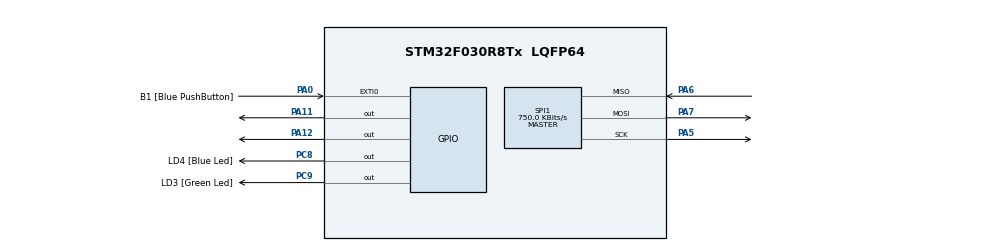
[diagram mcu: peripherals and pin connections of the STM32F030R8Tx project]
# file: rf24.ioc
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Mcu.Family=STM32F0
Mcu.Name=STM32F030R8Tx
Mcu.Package=LQFP64
PA0.GPIO_Label=B1 [Blue PushButton]
PA0.GPIO_ModeDefaultEXTI=GPIO_MODE_EVT_RISING
PA0.Signal=GPXTI0
PA11.PinState=GPIO_PIN_RESET
PA11.Signal=GPIO_Output
PA12.PinState=GPIO_PIN_SET
PA12.Signal=GPIO_Output
PA13.GPIO_Label=SWDIO
PA13.Mode=Serial_Wire
PA13.Signal=SYS_SWDIO
PA14.GPIO_Label=SWCLK
PA14.Mode=Serial_Wire
PA14.Signal=SYS_SWCLK
PA5.Mode=Full_Duplex_Master
PA5.Signal=SPI1_SCK
PA6.Mode=Full_Duplex_Master
PA6.Signal=SPI1_MISO
PA7.Mode=Full_Duplex_Master
PA7.Signal=SPI1_MOSI
PC8.GPIO_Label=LD4 [Blue Led]
PC8.Signal=GPIO_Output
PC9.GPIO_Label=LD3 [Green Led]
PC9.Signal=GPIO_Output
ProjectManager.HeapSize=0x200
ProjectManager.StackSize=0x400
ProjectManager.TargetToolchain=Makefile
RCC.AHBFreq_Value=48000000
RCC.APB1Freq_Value=48000000
RCC.APB1TimFreq_Value=48000000
RCC.HCLKFreq_Value=48000000
RCC.PLLMUL=RCC_PLL_MUL12
RCC.SYSCLKFreq_VALUE=48000000
RCC.SYSCLKSource=RCC_SYSCLKSOURCE_PLLCLK
SPI1.BaudRatePrescaler=SPI_BAUDRATEPRESCALER_64
SPI1.CLKPhase=SPI_PHASE_1EDGE
SPI1.CalculateBaudRate=750.0 KBits/s
SPI1.DataSize=SPI_DATASIZE_8BIT
SPI1.Direction=SPI_DIRECTION_2LINES
SPI1.Mode=SPI_MODE_MASTER
SPI1.NSSPMode=SPI_NSS_PULSE_DISABLE
SPI1.VirtualType=VM_MASTER
board=STM32F0308-DISCO

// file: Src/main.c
/* USER CODE BEGIN Header */
/**
  ******************************************************************************
  * @file           : main.c
  * @brief          : Main program body
  ******************************************************************************
  * @attention
  *
  * <h2><center>&copy; Copyright (c) 2020 STMicroelectronics.
  * All rights reserved.</center></h2>
  *
  * This software component is licensed by ST under BSD 3-Clause license,
  * the "License"; You may not use this file except in compliance with the
  * License. You may obtain a copy of the License at:
  *                        opensource.org/licenses/BSD-3-Clause
  *
  ******************************************************************************
  */
/* USER CODE END Header */

#include "main.h"

/* USER CODE BEGIN Includes */
#include <stdbool.h>
#include <stdint.h>
#include "rf24.h"
#include "stm32f0xx_hal.h"
#include "stm32f0xx_hal_spi.h"
/* USER CODE END Includes */

SPI_HandleTypeDef hspi1;

void SystemClock_Config(void);
static void MX_GPIO_Init(void);
static void MX_SPI1_Init(void);

int main(void)
{

  /* MCU Configuration--------------------------------------------------------*/

  /* Reset of all peripherals, Initializes the Flash interface and the Systick. */
  HAL_Init();

  /* Configure the system clock */
  SystemClock_Config();

  /* Initialize all configured peripherals */
  MX_GPIO_Init();
  MX_SPI1_Init();
  /* USER CODE BEGIN 2 */
  bool radioNumber = 0;

  uint8_t addresses[][6] = {"1Node", "2Node"};

  if (rf_begin() == true) {
    HAL_GPIO_WritePin(GPIOC, GPIO_PIN_9, GPIO_PIN_SET);
    uint8_t counter = 1;
    rf_enableAckPayload();
    rf_enableDynamicPayloads();

    if (radioNumber) {
      rf_openWritingPipe(addresses[1]); // Both radios listen on the same pipes
					// by default, but opposite addresses
      rf_openReadingPipe(
	  1, addresses[0]); // Open a reading pipe on address 0, pipe 1
    } else {
      rf_openWritingPipe(addresses[0]);
      rf_openReadingPipe(1, addresses[1]);
    }
    rf_startListening(); // Start listening

    rf_writeAckPayload(
	1, &counter,
	1); // Pre-load an ack-paylod into the FIFO buffer for pipe 1

    HAL_GPIO_WritePin(GPIOC, GPIO_PIN_9, GPIO_PIN_RESET);

    uint8_t spi_tfbuf[2];

    spi_tfbuf[0] = 0;
    spi_tfbuf[1] = 0;
    rf_stopListening();

    while (1) {
      rf_powerUp();

      rf_stopListening();

      if (rf_write(spi_tfbuf, 2) == 1) {

	HAL_GPIO_TogglePin(GPIOC, GPIO_PIN_9);
	spi_tfbuf[0]++;
	//	spi_tfbuf[1]++;
      }
      rf_powerDown();
      HAL_Delay(1000);
    }
  }

  /* USER CODE END 2 */

  /* Infinite loop */
  while (1)
  {

  }
}

void SystemClock_Config(void)
{
  RCC_OscInitTypeDef RCC_OscInitStruct = {0};
  RCC_ClkInitTypeDef RCC_ClkInitStruct = {0};

  /** Initializes the CPU, AHB and APB busses clocks
  */
  RCC_OscInitStruct.OscillatorType = RCC_OSCILLATORTYPE_HSI;
  RCC_OscInitStruct.HSIState = RCC_HSI_ON;
  RCC_OscInitStruct.HSICalibrationValue = RCC_HSICALIBRATION_DEFAULT;
  RCC_OscInitStruct.PLL.PLLState = RCC_PLL_ON;
  RCC_OscInitStruct.PLL.PLLSource = RCC_PLLSOURCE_HSI;
  RCC_OscInitStruct.PLL.PLLMUL = RCC_PLL_MUL16;
  RCC_OscInitStruct.PLL.PREDIV = RCC_PREDIV_DIV1;
  if (HAL_RCC_OscConfig(&RCC_OscInitStruct) != HAL_OK)
  {
    Error_Handler();
  }
  /** Initializes the CPU, AHB and APB busses clocks
  */
  RCC_ClkInitStruct.ClockType = RCC_CLOCKTYPE_HCLK|RCC_CLOCKTYPE_SYSCLK
                              |RCC_CLOCKTYPE_PCLK1;
  RCC_ClkInitStruct.SYSCLKSource = RCC_SYSCLKSOURCE_PLLCLK;
  RCC_ClkInitStruct.AHBCLKDivider = RCC_SYSCLK_DIV1;
  RCC_ClkInitStruct.APB1CLKDivider = RCC_HCLK_DIV1;

  if (HAL_RCC_ClockConfig(&RCC_ClkInitStruct, FLASH_LATENCY_1) != HAL_OK)
  {
    Error_Handler();
  }
}

static void MX_SPI1_Init(void)
{

  /* SPI1 parameter configuration*/

}

static void MX_GPIO_Init(void)
{
  GPIO_InitTypeDef GPIO_InitStruct = {0};

  /* GPIO Ports Clock Enable */
  __HAL_RCC_GPIOA_CLK_ENABLE();
  __HAL_RCC_GPIOC_CLK_ENABLE();

  /*Configure GPIO pin Output Level */
  HAL_GPIO_WritePin(GPIOC, LD4_Pin|LD3_Pin, GPIO_PIN_RESET);

  /*Configure GPIO pin Output Level */
  HAL_GPIO_WritePin(GPIOA, GPIO_PIN_11, GPIO_PIN_RESET);

  /*Configure GPIO pin Output Level */
  HAL_GPIO_WritePin(GPIOA, GPIO_PIN_12, GPIO_PIN_SET);

  /*Configure GPIO pin : B1_Pin */
  GPIO_InitStruct.Pin = B1_Pin;
  GPIO_InitStruct.Mode = GPIO_MODE_EVT_RISING;
  GPIO_InitStruct.Pull = GPIO_NOPULL;
  HAL_GPIO_Init(B1_GPIO_Port, &GPIO_InitStruct);

  /*Configure GPIO pins : LD4_Pin LD3_Pin */
  GPIO_InitStruct.Pin = LD4_Pin|LD3_Pin;
  GPIO_InitStruct.Mode = GPIO_MODE_OUTPUT_PP;
  GPIO_InitStruct.Pull = GPIO_NOPULL;
  GPIO_InitStruct.Speed = GPIO_SPEED_FREQ_LOW;
  HAL_GPIO_Init(GPIOC, &GPIO_InitStruct);

  /*Configure GPIO pins : PA11 PA12 */
  GPIO_InitStruct.Pin = GPIO_PIN_11|GPIO_PIN_12;
  GPIO_InitStruct.Mode = GPIO_MODE_OUTPUT_PP;
  GPIO_InitStruct.Pull = GPIO_NOPULL;
  GPIO_InitStruct.Speed = GPIO_SPEED_FREQ_LOW;
  HAL_GPIO_Init(GPIOA, &GPIO_InitStruct);

}

void Error_Handler(void)
{
}

/************************ (C) COPYRIGHT STMicroelectronics *****END OF FILE****/
